One B-rep face of a CAD part: STEP entity #38.
In plain terms, the planar face has unit normal (1, 0, 0).
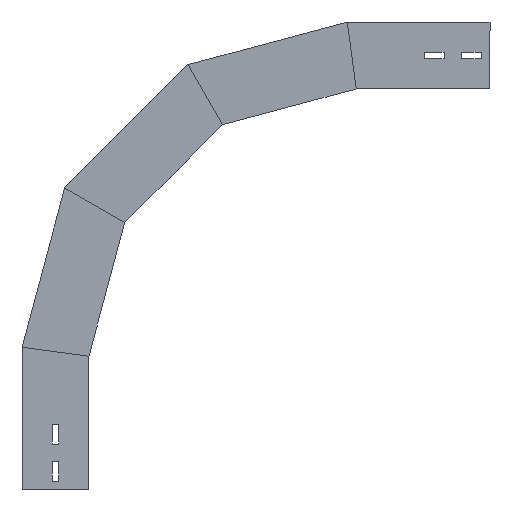
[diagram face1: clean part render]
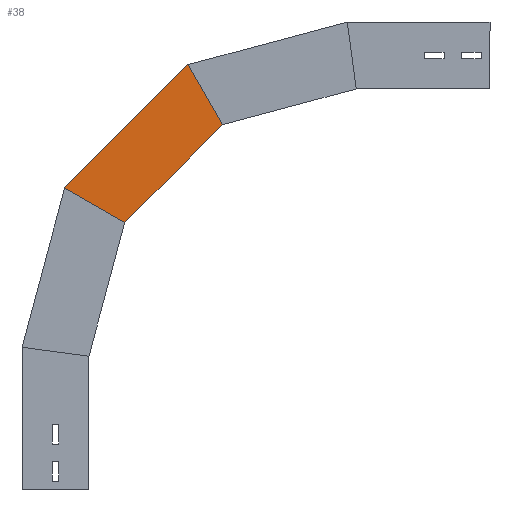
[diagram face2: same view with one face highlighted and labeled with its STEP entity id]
Its self-contained STEP definition (entity closure, numbers rounded to 3 decimals):
#38 = ADVANCED_FACE ( 'NONE', ( #892 ), #1191, .T. ) ;
#39 = LINE ( 'NONE', #207, #1129 ) ;
#144 = CARTESIAN_POINT ( 'NONE',  ( 0., -149.719, 409.32 ) ) ;
#165 = DIRECTION ( 'NONE',  ( 0., -0.5, -0.866 ) ) ;
#172 = DIRECTION ( 'NONE',  ( 0., -0.707, 0.707 ) ) ;
#207 = CARTESIAN_POINT ( 'NONE',  ( 0., 28.618, 337.05 ) ) ;
#311 = LINE ( 'NONE', #1341, #1139 ) ;
#313 = DIRECTION ( 'NONE',  ( 0., -0.707, 0.707 ) ) ;
#316 = ORIENTED_EDGE ( 'NONE', *, *, #1342, .F. ) ;
#318 = LINE ( 'NONE', #905, #1692 ) ;
#354 = EDGE_LOOP ( 'NONE', ( #1204, #743, #316, #1701 ) ) ;
#376 = LINE ( 'NONE', #1559, #1369 ) ;
#463 = DIRECTION ( 'NONE',  ( 1., 0., 0. ) ) ;
#472 = VERTEX_POINT ( 'NONE', #1327 ) ;
#487 = VERTEX_POINT ( 'NONE', #144 ) ;
#564 = CARTESIAN_POINT ( 'NONE',  ( 0., -24.415, 284.017 ) ) ;
#631 = AXIS2_PLACEMENT_3D ( 'NONE', #564, #463, #1043 ) ;
#667 = DIRECTION ( 'NONE',  ( 0., -0.866, -0.5 ) ) ;
#743 = ORIENTED_EDGE ( 'NONE', *, *, #879, .T. ) ;
#869 = VERTEX_POINT ( 'NONE', #1054 ) ;
#879 = EDGE_CURVE ( 'NONE', #869, #487, #311, .T. ) ;
#892 = FACE_OUTER_BOUND ( 'NONE', #354, .T. ) ;
#905 = CARTESIAN_POINT ( 'NONE',  ( 0., -24.415, 284.017 ) ) ;
#1043 = DIRECTION ( 'NONE',  ( 0., 0., -1. ) ) ;
#1054 = CARTESIAN_POINT ( 'NONE',  ( 0., -110.896, 476.563 ) ) ;
#1129 = VECTOR ( 'NONE', #313, 1000. ) ;
#1139 = VECTOR ( 'NONE', #165, 1000. ) ;
#1191 = PLANE ( 'NONE',  #631 ) ;
#1204 = ORIENTED_EDGE ( 'NONE', *, *, #1809, .T. ) ;
#1327 = CARTESIAN_POINT ( 'NONE',  ( 0., 27.126, 338.541 ) ) ;
#1341 = CARTESIAN_POINT ( 'NONE',  ( 0., -172.651, 369.6 ) ) ;
#1342 = EDGE_CURVE ( 'NONE', #1482, #487, #318, .T. ) ;
#1366 = CARTESIAN_POINT ( 'NONE',  ( 0., -40.117, 299.719 ) ) ;
#1369 = VECTOR ( 'NONE', #667, 1000. ) ;
#1482 = VERTEX_POINT ( 'NONE', #1366 ) ;
#1526 = EDGE_CURVE ( 'NONE', #472, #1482, #376, .T. ) ;
#1559 = CARTESIAN_POINT ( 'NONE',  ( 0., -77.316, 278.242 ) ) ;
#1692 = VECTOR ( 'NONE', #172, 1000. ) ;
#1701 = ORIENTED_EDGE ( 'NONE', *, *, #1526, .F. ) ;
#1809 = EDGE_CURVE ( 'NONE', #472, #869, #39, .T. ) ;
